VERSION 5.7 ;
  NAMESCASESENSITIVE ON ;
  NOWIREEXTENSIONATPIN ON ;
  DIVIDERCHAR "/" ;
  BUSBITCHARS "[]" ;
UNITS
  DATABASE MICRONS 200 ;
END UNITS

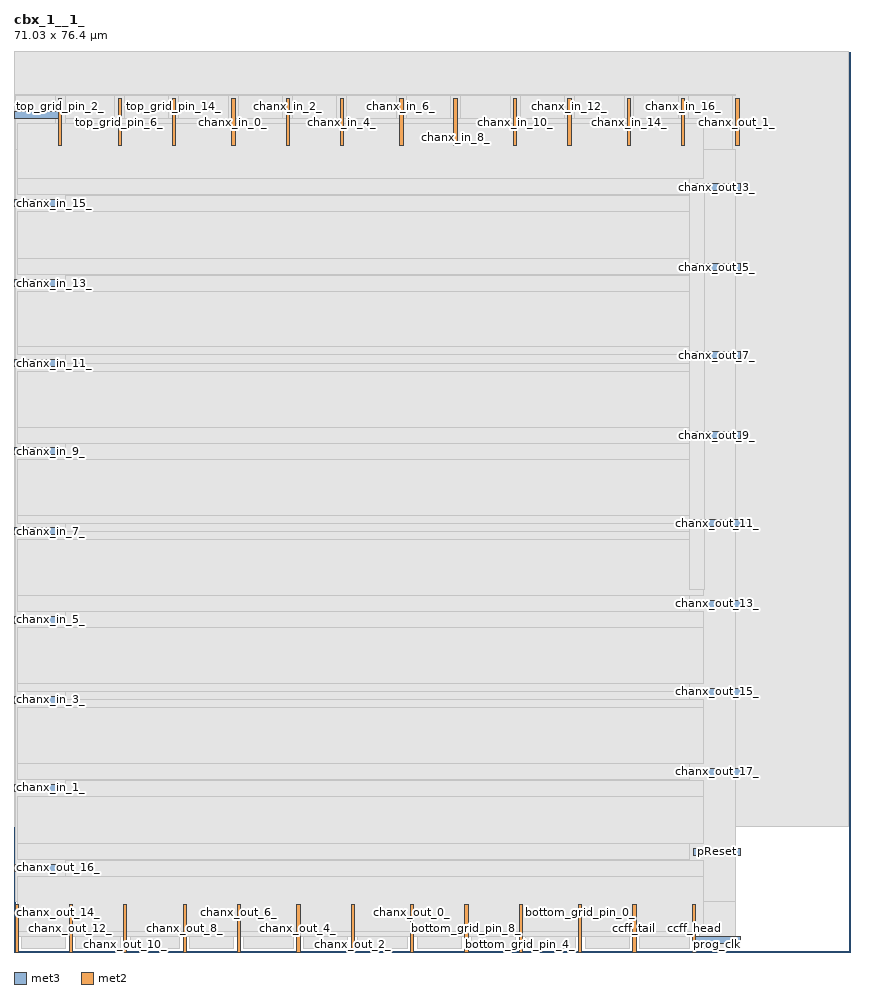
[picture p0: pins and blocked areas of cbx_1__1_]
MACRO cbx_1__1_
  CLASS BLOCK ;
  FOREIGN cbx_1__1_ ;
  ORIGIN 0.000 0.000 ;
  SIZE 71.030 BY 76.400 ;
  PIN chanx_out_7_
    DIRECTION OUTPUT TRISTATE ;
    PORT
      LAYER met3 ;
        RECT 57.710 50.360 61.710 50.960 ;
    END
  END chanx_out_7_
  PIN chanx_in_9_
    DIRECTION INPUT ;
    PORT
      LAYER met3 ;
        RECT 0.000 42.200 4.000 42.800 ;
    END
  END chanx_in_9_
  PIN chanx_in_5_
    DIRECTION INPUT ;
    PORT
      LAYER met3 ;
        RECT 0.000 27.920 4.000 28.520 ;
    END
  END chanx_in_5_
  PIN chanx_out_16_
    DIRECTION OUTPUT TRISTATE ;
    PORT
      LAYER met3 ;
        RECT 0.000 6.840 4.000 7.440 ;
    END
  END chanx_out_16_
  PIN top_grid_pin_6_
    DIRECTION OUTPUT TRISTATE ;
    PORT
      LAYER met2 ;
        RECT 8.830 68.430 9.110 72.430 ;
    END
  END top_grid_pin_6_
  PIN bottom_grid_pin_4_
    DIRECTION OUTPUT TRISTATE ;
    PORT
      LAYER met2 ;
        RECT 42.870 0.000 43.150 4.000 ;
    END
  END bottom_grid_pin_4_
  PIN ccff_tail
    DIRECTION OUTPUT TRISTATE ;
    PORT
      LAYER met2 ;
        RECT 52.530 0.000 52.810 4.000 ;
    END
  END ccff_tail
  PIN chanx_in_17_
    DIRECTION INPUT ;
    PORT
      LAYER met3 ;
        RECT 0.000 70.760 4.000 71.360 ;
    END
  END chanx_in_17_
  PIN chanx_in_16_
    DIRECTION INPUT ;
    PORT
      LAYER met2 ;
        RECT 56.670 68.430 56.950 72.430 ;
    END
  END chanx_in_16_
  PIN chanx_in_10_
    DIRECTION INPUT ;
    PORT
      LAYER met2 ;
        RECT 42.410 68.430 42.690 72.430 ;
    END
  END chanx_in_10_
  PIN chanx_out_3_
    DIRECTION OUTPUT TRISTATE ;
    PORT
      LAYER met3 ;
        RECT 57.710 64.640 61.710 65.240 ;
    END
  END chanx_out_3_
  PIN chanx_in_3_
    DIRECTION INPUT ;
    PORT
      LAYER met3 ;
        RECT 0.000 21.120 4.000 21.720 ;
    END
  END chanx_in_3_
  PIN ccff_head
    DIRECTION INPUT ;
    PORT
      LAYER met2 ;
        RECT 57.590 0.000 57.870 4.000 ;
    END
  END ccff_head
  PIN chanx_in_7_
    DIRECTION INPUT ;
    PORT
      LAYER met3 ;
        RECT 0.000 35.400 4.000 36.000 ;
    END
  END chanx_in_7_
  PIN top_grid_pin_14_
    DIRECTION OUTPUT TRISTATE ;
    PORT
      LAYER met2 ;
        RECT 13.430 68.430 13.710 72.430 ;
    END
  END top_grid_pin_14_
  PIN chanx_out_10_
    DIRECTION OUTPUT TRISTATE ;
    PORT
      LAYER met2 ;
        RECT 9.290 0.000 9.570 4.000 ;
    END
  END chanx_out_10_
  PIN chanx_out_13_
    DIRECTION OUTPUT TRISTATE ;
    PORT
      LAYER met3 ;
        RECT 57.710 29.280 61.710 29.880 ;
    END
  END chanx_out_13_
  PIN chanx_in_2_
    DIRECTION INPUT ;
    PORT
      LAYER met2 ;
        RECT 23.090 68.430 23.370 72.430 ;
    END
  END chanx_in_2_
  PIN chanx_out_9_
    DIRECTION OUTPUT TRISTATE ;
    PORT
      LAYER met3 ;
        RECT 57.710 43.560 61.710 44.160 ;
    END
  END chanx_out_9_
  PIN chanx_in_14_
    DIRECTION INPUT ;
    PORT
      LAYER met2 ;
        RECT 52.070 68.430 52.350 72.430 ;
    END
  END chanx_in_14_
  PIN chanx_out_15_
    DIRECTION OUTPUT TRISTATE ;
    PORT
      LAYER met3 ;
        RECT 57.710 21.800 61.710 22.400 ;
    END
  END chanx_out_15_
  PIN chanx_in_11_
    DIRECTION INPUT ;
    PORT
      LAYER met3 ;
        RECT 0.000 49.680 4.000 50.280 ;
    END
  END chanx_in_11_
  PIN chanx_in_4_
    DIRECTION INPUT ;
    PORT
      LAYER met2 ;
        RECT 27.690 68.430 27.970 72.430 ;
    END
  END chanx_in_4_
  PIN chanx_out_17_
    DIRECTION OUTPUT TRISTATE ;
    PORT
      LAYER met3 ;
        RECT 57.710 15.000 61.710 15.600 ;
    END
  END chanx_out_17_
  PIN top_grid_pin_2_
    DIRECTION OUTPUT TRISTATE ;
    PORT
      LAYER met2 ;
        RECT 3.770 68.430 4.050 72.430 ;
    END
  END top_grid_pin_2_
  PIN chanx_out_4_
    DIRECTION OUTPUT TRISTATE ;
    PORT
      LAYER met2 ;
        RECT 24.010 0.000 24.290 4.000 ;
    END
  END chanx_out_4_
  PIN chanx_in_15_
    DIRECTION INPUT ;
    PORT
      LAYER met3 ;
        RECT 0.000 63.280 4.000 63.880 ;
    END
  END chanx_in_15_
  PIN pReset
    DIRECTION INPUT ;
    PORT
      LAYER met3 ;
        RECT 57.710 8.200 61.710 8.800 ;
    END
  END pReset
  PIN chanx_in_8_
    DIRECTION INPUT ;
    PORT
      LAYER met2 ;
        RECT 37.350 68.430 37.630 72.430 ;
    END
  END chanx_in_8_
  PIN chanx_in_1_
    DIRECTION INPUT ;
    PORT
      LAYER met3 ;
        RECT 0.000 13.640 4.000 14.240 ;
    END
  END chanx_in_1_
  PIN chanx_out_0_
    DIRECTION OUTPUT TRISTATE ;
    PORT
      LAYER met2 ;
        RECT 33.670 0.000 33.950 4.000 ;
    END
  END chanx_out_0_
  PIN chanx_out_1_
    DIRECTION OUTPUT TRISTATE ;
    PORT
      LAYER met2 ;
        RECT 61.270 68.430 61.550 72.430 ;
    END
  END chanx_out_1_
  PIN chanx_in_6_
    DIRECTION INPUT ;
    PORT
      LAYER met2 ;
        RECT 32.750 68.430 33.030 72.430 ;
    END
  END chanx_in_6_
  PIN chanx_in_12_
    DIRECTION INPUT ;
    PORT
      LAYER met2 ;
        RECT 47.010 68.430 47.290 72.430 ;
    END
  END chanx_in_12_
  PIN chanx_out_11_
    DIRECTION OUTPUT TRISTATE ;
    PORT
      LAYER met3 ;
        RECT 57.710 36.080 61.710 36.680 ;
    END
  END chanx_out_11_
  PIN chanx_out_6_
    DIRECTION OUTPUT TRISTATE ;
    PORT
      LAYER met2 ;
        RECT 18.950 0.000 19.230 4.000 ;
    END
  END chanx_out_6_
  PIN chanx_out_8_
    DIRECTION OUTPUT TRISTATE ;
    PORT
      LAYER met2 ;
        RECT 14.350 0.000 14.630 4.000 ;
    END
  END chanx_out_8_
  PIN prog_clk
    DIRECTION INPUT ;
    PORT
      LAYER met3 ;
        RECT 57.710 0.720 61.710 1.320 ;
    END
  END prog_clk
  PIN bottom_grid_pin_0_
    DIRECTION OUTPUT TRISTATE ;
    PORT
      LAYER met2 ;
        RECT 47.930 0.000 48.210 4.000 ;
    END
  END bottom_grid_pin_0_
  PIN bottom_grid_pin_8_
    DIRECTION OUTPUT TRISTATE ;
    PORT
      LAYER met2 ;
        RECT 38.270 0.000 38.550 4.000 ;
    END
  END bottom_grid_pin_8_
  PIN chanx_out_2_
    DIRECTION OUTPUT TRISTATE ;
    PORT
      LAYER met2 ;
        RECT 28.610 0.000 28.890 4.000 ;
    END
  END chanx_out_2_
  PIN chanx_in_13_
    DIRECTION INPUT ;
    PORT
      LAYER met3 ;
        RECT 0.000 56.480 4.000 57.080 ;
    END
  END chanx_in_13_
  PIN chanx_out_12_
    DIRECTION OUTPUT TRISTATE ;
    PORT
      LAYER met2 ;
        RECT 4.690 0.000 4.970 4.000 ;
    END
  END chanx_out_12_
  PIN chanx_in_0_
    DIRECTION INPUT ;
    PORT
      LAYER met2 ;
        RECT 18.490 68.430 18.770 72.430 ;
    END
  END chanx_in_0_
  PIN chanx_out_5_
    DIRECTION OUTPUT TRISTATE ;
    PORT
      LAYER met3 ;
        RECT 57.710 57.840 61.710 58.440 ;
    END
  END chanx_out_5_
  PIN chanx_out_14_
    DIRECTION OUTPUT TRISTATE ;
    PORT
      LAYER met2 ;
        RECT 0.090 0.000 0.370 4.000 ;
    END
  END chanx_out_14_
  OBS
      LAYER li1 ;
        RECT 5.520 10.795 70.840 76.245 ;
      LAYER met1 ;
        RECT 0.070 10.640 70.840 76.400 ;
      LAYER met2 ;
        RECT 0.090 72.710 61.270 72.750 ;
        RECT 0.090 68.150 3.490 72.710 ;
        RECT 4.330 68.150 8.550 72.710 ;
        RECT 9.390 68.150 13.150 72.710 ;
        RECT 13.990 68.150 18.210 72.710 ;
        RECT 19.050 68.150 22.810 72.710 ;
        RECT 23.650 68.150 27.410 72.710 ;
        RECT 28.250 68.150 32.470 72.710 ;
        RECT 33.310 68.150 37.070 72.710 ;
        RECT 37.910 68.150 42.130 72.710 ;
        RECT 42.970 68.150 46.730 72.710 ;
        RECT 47.570 68.150 51.790 72.710 ;
        RECT 52.630 68.150 56.390 72.710 ;
        RECT 57.230 68.150 60.990 72.710 ;
        RECT 0.090 4.280 61.270 68.150 ;
        RECT 0.650 0.270 4.410 4.280 ;
        RECT 5.250 0.270 9.010 4.280 ;
        RECT 9.850 0.270 14.070 4.280 ;
        RECT 14.910 0.270 18.670 4.280 ;
        RECT 19.510 0.270 23.730 4.280 ;
        RECT 24.570 0.270 28.330 4.280 ;
        RECT 29.170 0.270 33.390 4.280 ;
        RECT 34.230 0.270 37.990 4.280 ;
        RECT 38.830 0.270 42.590 4.280 ;
        RECT 43.430 0.270 47.650 4.280 ;
        RECT 48.490 0.270 52.250 4.280 ;
        RECT 53.090 0.270 57.310 4.280 ;
        RECT 58.150 0.270 61.270 4.280 ;
      LAYER met3 ;
        RECT 4.400 70.360 58.570 70.760 ;
        RECT 0.310 65.640 58.570 70.360 ;
        RECT 0.310 64.280 57.310 65.640 ;
        RECT 4.400 64.240 57.310 64.280 ;
        RECT 4.400 62.880 58.570 64.240 ;
        RECT 0.310 58.840 58.570 62.880 ;
        RECT 0.310 57.480 57.310 58.840 ;
        RECT 4.400 57.440 57.310 57.480 ;
        RECT 4.400 56.080 58.570 57.440 ;
        RECT 0.310 51.360 58.570 56.080 ;
        RECT 0.310 50.680 57.310 51.360 ;
        RECT 4.400 49.960 57.310 50.680 ;
        RECT 4.400 49.280 58.570 49.960 ;
        RECT 0.310 44.560 58.570 49.280 ;
        RECT 0.310 43.200 57.310 44.560 ;
        RECT 4.400 43.160 57.310 43.200 ;
        RECT 4.400 41.800 58.570 43.160 ;
        RECT 0.310 37.080 58.570 41.800 ;
        RECT 0.310 36.400 57.310 37.080 ;
        RECT 4.400 35.680 57.310 36.400 ;
        RECT 4.400 35.000 58.570 35.680 ;
        RECT 0.310 30.280 58.570 35.000 ;
        RECT 0.310 28.920 57.310 30.280 ;
        RECT 4.400 28.880 57.310 28.920 ;
        RECT 4.400 27.520 58.570 28.880 ;
        RECT 0.310 22.800 58.570 27.520 ;
        RECT 0.310 22.120 57.310 22.800 ;
        RECT 4.400 21.400 57.310 22.120 ;
        RECT 4.400 20.720 58.570 21.400 ;
        RECT 0.310 16.000 58.570 20.720 ;
        RECT 0.310 14.640 57.310 16.000 ;
        RECT 4.400 14.600 57.310 14.640 ;
        RECT 4.400 13.240 58.570 14.600 ;
        RECT 0.310 9.200 58.570 13.240 ;
        RECT 0.310 7.840 57.310 9.200 ;
        RECT 4.400 7.800 57.310 7.840 ;
        RECT 4.400 6.440 58.570 7.800 ;
        RECT 0.310 1.720 58.570 6.440 ;
        RECT 0.310 1.320 57.310 1.720 ;
      LAYER met4 ;
        RECT 57.335 30.775 58.585 65.105 ;
  END
END cbx_1__1_
END LIBRARY

